One B-rep face of a CAD part: STEP entity #1240.
In plain terms, the planar face has unit normal (1, 0, 0).
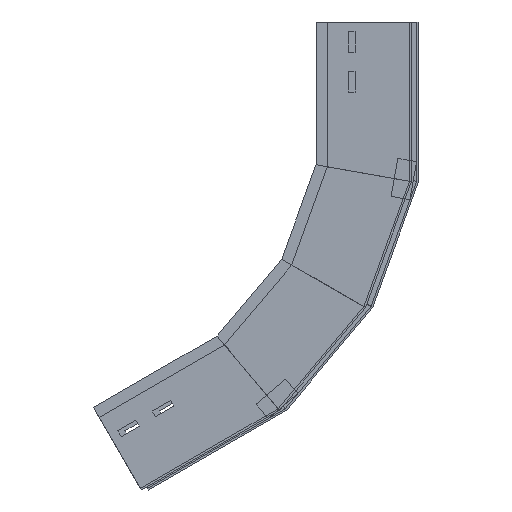
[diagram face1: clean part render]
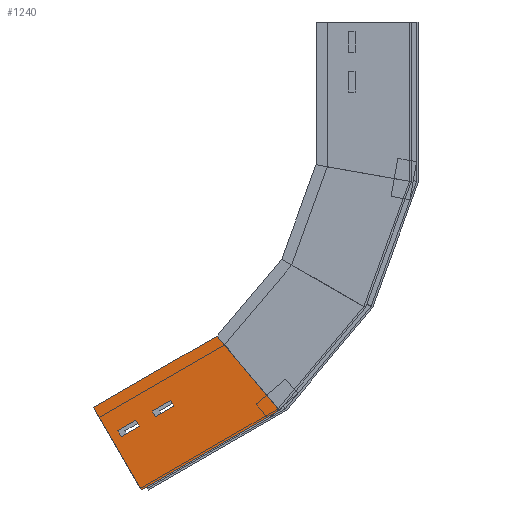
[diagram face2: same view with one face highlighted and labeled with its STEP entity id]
Its self-contained STEP definition (entity closure, numbers rounded to 3 decimals):
#20 = CARTESIAN_POINT ( 'NONE',  ( 0., 0., -167.4 ) ) ;
#70 = CARTESIAN_POINT ( 'NONE',  ( 0., 59., -31.835 ) ) ;
#77 = VECTOR ( 'NONE', #1147, 1000. ) ;
#98 = CARTESIAN_POINT ( 'NONE',  ( 0., 59., -51.505 ) ) ;
#100 = VERTEX_POINT ( 'NONE', #1306 ) ;
#119 = FACE_OUTER_BOUND ( 'NONE', #1041, .T. ) ;
#131 = EDGE_CURVE ( 'NONE', #1441, #543, #1247, .T. ) ;
#180 = ORIENTED_EDGE ( 'NONE', *, *, #193, .T. ) ;
#193 = EDGE_CURVE ( 'NONE', #315, #100, #726, .T. ) ;
#197 = DIRECTION ( 'NONE',  ( 0., 0., -1. ) ) ;
#202 = DIRECTION ( 'NONE',  ( 0., 1., 0. ) ) ;
#250 = CARTESIAN_POINT ( 'NONE',  ( 0., 66., -51.505 ) ) ;
#251 = EDGE_LOOP ( 'NONE', ( #421, #180, #1125, #330 ) ) ;
#270 = EDGE_CURVE ( 'NONE', #543, #519, #359, .T. ) ;
#276 = FACE_BOUND ( 'NONE', #251, .T. ) ;
#277 = DIRECTION ( 'NONE',  ( 0., 0., -1. ) ) ;
#315 = VERTEX_POINT ( 'NONE', #1002 ) ;
#330 = ORIENTED_EDGE ( 'NONE', *, *, #1639, .T. ) ;
#345 = VECTOR ( 'NONE', #1643, 1000. ) ;
#347 = ORIENTED_EDGE ( 'NONE', *, *, #1063, .T. ) ;
#359 = LINE ( 'NONE', #98, #765 ) ;
#388 = EDGE_CURVE ( 'NONE', #100, #532, #682, .T. ) ;
#395 = VECTOR ( 'NONE', #277, 1000. ) ;
#421 = ORIENTED_EDGE ( 'NONE', *, *, #643, .T. ) ;
#427 = VECTOR ( 'NONE', #197, 1000. ) ;
#432 = VERTEX_POINT ( 'NONE', #1331 ) ;
#465 = CARTESIAN_POINT ( 'NONE',  ( 0., 59., -9.835 ) ) ;
#471 = DIRECTION ( 'NONE',  ( 0., 0., -1. ) ) ;
#483 = ORIENTED_EDGE ( 'NONE', *, *, #1035, .F. ) ;
#484 = VECTOR ( 'NONE', #741, 1000. ) ;
#493 = DIRECTION ( 'NONE',  ( 0., 1., 0. ) ) ;
#501 = CARTESIAN_POINT ( 'NONE',  ( 0., 100., -149.767 ) ) ;
#519 = VERTEX_POINT ( 'NONE', #724 ) ;
#532 = VERTEX_POINT ( 'NONE', #70 ) ;
#543 = VERTEX_POINT ( 'NONE', #1505 ) ;
#574 = VECTOR ( 'NONE', #1219, 1000. ) ;
#637 = CARTESIAN_POINT ( 'NONE',  ( 0., 66., -9.835 ) ) ;
#643 = EDGE_CURVE ( 'NONE', #990, #315, #1680, .T. ) ;
#649 = VECTOR ( 'NONE', #666, 1000. ) ;
#660 = DIRECTION ( 'NONE',  ( -1., 0., 0. ) ) ;
#661 = VERTEX_POINT ( 'NONE', #501 ) ;
#666 = DIRECTION ( 'NONE',  ( 0., 0., 1. ) ) ;
#682 = LINE ( 'NONE', #710, #574 ) ;
#687 = CARTESIAN_POINT ( 'NONE',  ( 0., 59., -9.835 ) ) ;
#710 = CARTESIAN_POINT ( 'NONE',  ( 0., 66., -31.835 ) ) ;
#724 = CARTESIAN_POINT ( 'NONE',  ( 0., 59., -51.505 ) ) ;
#726 = LINE ( 'NONE', #1373, #427 ) ;
#741 = DIRECTION ( 'NONE',  ( 0., 0., -1. ) ) ;
#744 = ORIENTED_EDGE ( 'NONE', *, *, #1054, .T. ) ;
#749 = CARTESIAN_POINT ( 'NONE',  ( 0., 100., 0. ) ) ;
#763 = VECTOR ( 'NONE', #471, 1000. ) ;
#765 = VECTOR ( 'NONE', #1519, 1000. ) ;
#770 = DIRECTION ( 'NONE',  ( 0., 0., 1. ) ) ;
#783 = EDGE_CURVE ( 'NONE', #661, #1439, #1463, .T. ) ;
#795 = ORIENTED_EDGE ( 'NONE', *, *, #131, .T. ) ;
#814 = AXIS2_PLACEMENT_3D ( 'NONE', #1307, #660, #770 ) ;
#933 = LINE ( 'NONE', #687, #649 ) ;
#960 = LINE ( 'NONE', #1336, #395 ) ;
#990 = VERTEX_POINT ( 'NONE', #465 ) ;
#991 = CARTESIAN_POINT ( 'NONE',  ( 0., 66., -73.505 ) ) ;
#994 = CARTESIAN_POINT ( 'NONE',  ( 0., 28.627, -162.352 ) ) ;
#1002 = CARTESIAN_POINT ( 'NONE',  ( 0., 66., -9.835 ) ) ;
#1011 = CARTESIAN_POINT ( 'NONE',  ( 0., 0., 0. ) ) ;
#1028 = EDGE_LOOP ( 'NONE', ( #744, #1419, #795, #1400 ) ) ;
#1035 = EDGE_CURVE ( 'NONE', #1305, #432, #1096, .T. ) ;
#1038 = PLANE ( 'NONE',  #814 ) ;
#1041 = EDGE_LOOP ( 'NONE', ( #1407, #483, #347, #1612 ) ) ;
#1054 = EDGE_CURVE ( 'NONE', #519, #1313, #1140, .T. ) ;
#1063 = EDGE_CURVE ( 'NONE', #1305, #1439, #1530, .T. ) ;
#1096 = LINE ( 'NONE', #1228, #1267 ) ;
#1116 = EDGE_CURVE ( 'NONE', #432, #661, #1353, .T. ) ;
#1125 = ORIENTED_EDGE ( 'NONE', *, *, #388, .T. ) ;
#1140 = LINE ( 'NONE', #1666, #1378 ) ;
#1147 = DIRECTION ( 'NONE',  ( 0., 1., 0. ) ) ;
#1150 = CARTESIAN_POINT ( 'NONE',  ( 0., 0., 0. ) ) ;
#1214 = DIRECTION ( 'NONE',  ( 0., -1., 0. ) ) ;
#1219 = DIRECTION ( 'NONE',  ( 0., -1., 0. ) ) ;
#1228 = CARTESIAN_POINT ( 'NONE',  ( 0., 0., 0. ) ) ;
#1240 = ADVANCED_FACE ( 'NONE', ( #1536, #119, #276 ), #1038, .F. ) ;
#1247 = LINE ( 'NONE', #991, #1460 ) ;
#1267 = VECTOR ( 'NONE', #202, 1000. ) ;
#1305 = VERTEX_POINT ( 'NONE', #1150 ) ;
#1306 = CARTESIAN_POINT ( 'NONE',  ( 0., 66., -31.835 ) ) ;
#1307 = CARTESIAN_POINT ( 'NONE',  ( 0., 0., 0. ) ) ;
#1313 = VERTEX_POINT ( 'NONE', #250 ) ;
#1331 = CARTESIAN_POINT ( 'NONE',  ( 0., 100., 0. ) ) ;
#1336 = CARTESIAN_POINT ( 'NONE',  ( 0., 66., -51.505 ) ) ;
#1353 = LINE ( 'NONE', #749, #484 ) ;
#1373 = CARTESIAN_POINT ( 'NONE',  ( 0., 66., -9.835 ) ) ;
#1378 = VECTOR ( 'NONE', #493, 1000. ) ;
#1400 = ORIENTED_EDGE ( 'NONE', *, *, #270, .T. ) ;
#1407 = ORIENTED_EDGE ( 'NONE', *, *, #1116, .F. ) ;
#1419 = ORIENTED_EDGE ( 'NONE', *, *, #1615, .T. ) ;
#1439 = VERTEX_POINT ( 'NONE', #20 ) ;
#1441 = VERTEX_POINT ( 'NONE', #1447 ) ;
#1447 = CARTESIAN_POINT ( 'NONE',  ( 0., 66., -73.505 ) ) ;
#1460 = VECTOR ( 'NONE', #1214, 1000. ) ;
#1463 = LINE ( 'NONE', #994, #345 ) ;
#1505 = CARTESIAN_POINT ( 'NONE',  ( 0., 59., -73.505 ) ) ;
#1519 = DIRECTION ( 'NONE',  ( 0., 0., 1. ) ) ;
#1530 = LINE ( 'NONE', #1011, #763 ) ;
#1536 = FACE_BOUND ( 'NONE', #1028, .T. ) ;
#1612 = ORIENTED_EDGE ( 'NONE', *, *, #783, .F. ) ;
#1615 = EDGE_CURVE ( 'NONE', #1313, #1441, #960, .T. ) ;
#1639 = EDGE_CURVE ( 'NONE', #532, #990, #933, .T. ) ;
#1643 = DIRECTION ( 'NONE',  ( 0., -0.985, -0.174 ) ) ;
#1666 = CARTESIAN_POINT ( 'NONE',  ( 0., 66., -51.505 ) ) ;
#1680 = LINE ( 'NONE', #637, #77 ) ;
